VERSION 5.7 ;
  NOWIREEXTENSIONATPIN ON ;
  DIVIDERCHAR "/" ;
  BUSBITCHARS "[]" ;
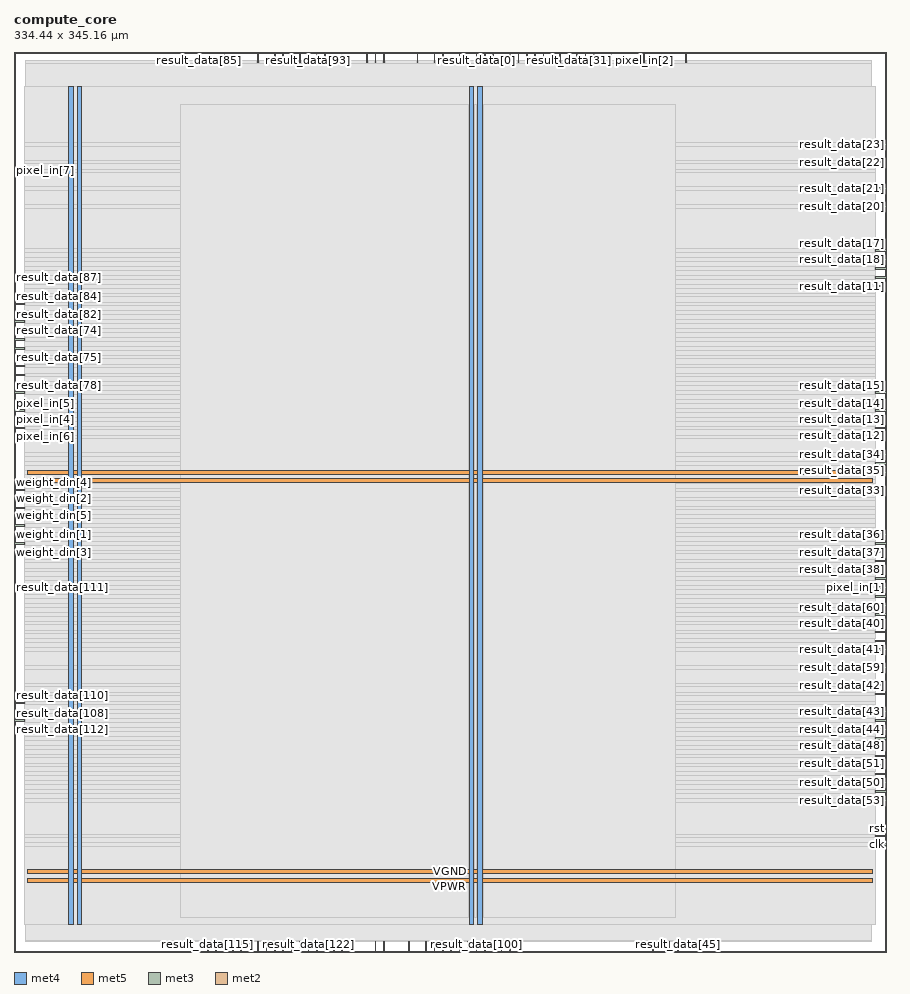
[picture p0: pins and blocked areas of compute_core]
MACRO compute_core
  CLASS BLOCK ;
  FOREIGN compute_core ;
  ORIGIN 0.000 0.000 ;
  SIZE 334.440 BY 345.160 ;
  PIN VGND
    DIRECTION INOUT ;
    USE GROUND ;
    PORT
      LAYER met4 ;
        RECT 24.340 10.640 25.940 332.080 ;
    END
    PORT
      LAYER met4 ;
        RECT 177.940 10.640 179.540 332.080 ;
    END
    PORT
      LAYER met5 ;
        RECT 5.280 30.030 329.140 31.630 ;
    END
    PORT
      LAYER met5 ;
        RECT 5.280 183.210 329.140 184.810 ;
    END
  END VGND
  PIN VPWR
    DIRECTION INOUT ;
    USE POWER ;
    PORT
      LAYER met4 ;
        RECT 21.040 10.640 22.640 332.080 ;
    END
    PORT
      LAYER met4 ;
        RECT 174.640 10.640 176.240 332.080 ;
    END
    PORT
      LAYER met5 ;
        RECT 5.280 26.730 329.140 28.330 ;
    END
    PORT
      LAYER met5 ;
        RECT 5.280 179.910 329.140 181.510 ;
    END
  END VPWR
  PIN clk
    DIRECTION INPUT ;
    USE SIGNAL ;
    ANTENNAGATEAREA 0.852000 ;
    PORT
      LAYER met3 ;
        RECT 330.440 40.840 334.440 41.440 ;
    END
  END clk
  PIN pixel_in[0]
    DIRECTION INPUT ;
    USE SIGNAL ;
    ANTENNAGATEAREA 0.213000 ;
    PORT
      LAYER met3 ;
        RECT 330.440 122.440 334.440 123.040 ;
    END
  END pixel_in[0]
  PIN pixel_in[1]
    DIRECTION INPUT ;
    USE SIGNAL ;
    ANTENNAGATEAREA 0.742500 ;
    PORT
      LAYER met3 ;
        RECT 330.440 139.440 334.440 140.040 ;
    END
  END pixel_in[1]
  PIN pixel_in[2]
    DIRECTION INPUT ;
    USE SIGNAL ;
    ANTENNAGATEAREA 0.213000 ;
    PORT
      LAYER met2 ;
        RECT 241.590 341.160 241.870 345.160 ;
    END
  END pixel_in[2]
  PIN pixel_in[3]
    DIRECTION INPUT ;
    USE SIGNAL ;
    ANTENNAGATEAREA 0.495000 ;
    PORT
      LAYER met3 ;
        RECT 0.000 200.640 4.000 201.240 ;
    END
  END pixel_in[3]
  PIN pixel_in[4]
    DIRECTION INPUT ;
    USE SIGNAL ;
    ANTENNAGATEAREA 0.213000 ;
    PORT
      LAYER met3 ;
        RECT 0.000 204.040 4.000 204.640 ;
    END
  END pixel_in[4]
  PIN pixel_in[5]
    DIRECTION INPUT ;
    USE SIGNAL ;
    ANTENNAGATEAREA 0.495000 ;
    PORT
      LAYER met3 ;
        RECT 0.000 207.440 4.000 208.040 ;
    END
  END pixel_in[5]
  PIN pixel_in[6]
    DIRECTION INPUT ;
    USE SIGNAL ;
    ANTENNAGATEAREA 0.196500 ;
    PORT
      LAYER met3 ;
        RECT 0.000 197.240 4.000 197.840 ;
    END
  END pixel_in[6]
  PIN pixel_in[7]
    DIRECTION INPUT ;
    USE SIGNAL ;
    ANTENNAGATEAREA 0.742500 ;
    PORT
      LAYER met3 ;
        RECT 0.000 299.240 4.000 299.840 ;
    END
  END pixel_in[7]
  PIN result_data[0]
    DIRECTION OUTPUT ;
    USE SIGNAL ;
    ANTENNADIFFAREA 0.445500 ;
    PORT
      LAYER met2 ;
        RECT 177.190 341.160 177.470 345.160 ;
    END
  END result_data[0]
  PIN result_data[100]
    DIRECTION OUTPUT ;
    USE SIGNAL ;
    ANTENNADIFFAREA 0.445500 ;
    PORT
      LAYER met2 ;
        RECT 177.190 0.000 177.470 4.000 ;
    END
  END result_data[100]
  PIN result_data[101]
    DIRECTION OUTPUT ;
    USE SIGNAL ;
    ANTENNADIFFAREA 0.445500 ;
    PORT
      LAYER met2 ;
        RECT 164.310 0.000 164.590 4.000 ;
    END
  END result_data[101]
  PIN result_data[102]
    DIRECTION OUTPUT ;
    USE SIGNAL ;
    ANTENNADIFFAREA 0.445500 ;
    PORT
      LAYER met2 ;
        RECT 151.430 0.000 151.710 4.000 ;
    END
  END result_data[102]
  PIN result_data[103]
    DIRECTION OUTPUT ;
    USE SIGNAL ;
    ANTENNADIFFAREA 0.445500 ;
    PORT
      LAYER met2 ;
        RECT 141.770 0.000 142.050 4.000 ;
    END
  END result_data[103]
  PIN result_data[104]
    DIRECTION OUTPUT ;
    USE SIGNAL ;
    ANTENNADIFFAREA 0.445500 ;
    PORT
      LAYER met2 ;
        RECT 138.550 0.000 138.830 4.000 ;
    END
  END result_data[104]
  PIN result_data[105]
    DIRECTION OUTPUT ;
    USE SIGNAL ;
    ANTENNADIFFAREA 0.445500 ;
    PORT
      LAYER met2 ;
        RECT 125.670 0.000 125.950 4.000 ;
    END
  END result_data[105]
  PIN result_data[106]
    DIRECTION OUTPUT ;
    USE SIGNAL ;
    ANTENNADIFFAREA 0.445500 ;
    PORT
      LAYER met2 ;
        RECT 109.570 0.000 109.850 4.000 ;
    END
  END result_data[106]
  PIN result_data[107]
    DIRECTION OUTPUT ;
    USE SIGNAL ;
    ANTENNADIFFAREA 0.445500 ;
    PORT
      LAYER met2 ;
        RECT 103.130 0.000 103.410 4.000 ;
    END
  END result_data[107]
  PIN result_data[108]
    DIRECTION OUTPUT ;
    USE SIGNAL ;
    ANTENNADIFFAREA 0.445500 ;
    PORT
      LAYER met3 ;
        RECT 0.000 88.440 4.000 89.040 ;
    END
  END result_data[108]
  PIN result_data[109]
    DIRECTION OUTPUT ;
    USE SIGNAL ;
    ANTENNADIFFAREA 0.445500 ;
    PORT
      LAYER met2 ;
        RECT 90.250 0.000 90.530 4.000 ;
    END
  END result_data[109]
  PIN result_data[10]
    DIRECTION OUTPUT ;
    USE SIGNAL ;
    ANTENNADIFFAREA 0.445500 ;
    PORT
      LAYER met3 ;
        RECT 330.440 261.840 334.440 262.440 ;
    END
  END result_data[10]
  PIN result_data[110]
    DIRECTION OUTPUT ;
    USE SIGNAL ;
    ANTENNADIFFAREA 0.445500 ;
    PORT
      LAYER met3 ;
        RECT 0.000 95.240 4.000 95.840 ;
    END
  END result_data[110]
  PIN result_data[111]
    DIRECTION OUTPUT ;
    USE SIGNAL ;
    ANTENNADIFFAREA 0.445500 ;
    PORT
      LAYER met3 ;
        RECT 0.000 139.440 4.000 140.040 ;
    END
  END result_data[111]
  PIN result_data[112]
    DIRECTION OUTPUT ;
    USE SIGNAL ;
    ANTENNADIFFAREA 0.445500 ;
    PORT
      LAYER met3 ;
        RECT 0.000 85.040 4.000 85.640 ;
    END
  END result_data[112]
  PIN result_data[113]
    DIRECTION OUTPUT ;
    USE SIGNAL ;
    ANTENNADIFFAREA 0.445500 ;
    PORT
      LAYER met2 ;
        RECT 80.590 0.000 80.870 4.000 ;
    END
  END result_data[113]
  PIN result_data[114]
    DIRECTION OUTPUT ;
    USE SIGNAL ;
    ANTENNADIFFAREA 0.445500 ;
    PORT
      LAYER met2 ;
        RECT 93.470 0.000 93.750 4.000 ;
    END
  END result_data[114]
  PIN result_data[115]
    DIRECTION OUTPUT ;
    USE SIGNAL ;
    ANTENNADIFFAREA 0.445500 ;
    PORT
      LAYER met2 ;
        RECT 74.150 0.000 74.430 4.000 ;
    END
  END result_data[115]
  PIN result_data[116]
    DIRECTION OUTPUT ;
    USE SIGNAL ;
    ANTENNADIFFAREA 0.445500 ;
    PORT
      LAYER met2 ;
        RECT 77.370 0.000 77.650 4.000 ;
    END
  END result_data[116]
  PIN result_data[117]
    DIRECTION OUTPUT ;
    USE SIGNAL ;
    ANTENNADIFFAREA 0.445500 ;
    PORT
      LAYER met2 ;
        RECT 87.030 0.000 87.310 4.000 ;
    END
  END result_data[117]
  PIN result_data[118]
    DIRECTION OUTPUT ;
    USE SIGNAL ;
    ANTENNADIFFAREA 0.445500 ;
    PORT
      LAYER met2 ;
        RECT 83.810 0.000 84.090 4.000 ;
    END
  END result_data[118]
  PIN result_data[119]
    DIRECTION OUTPUT ;
    USE SIGNAL ;
    ANTENNADIFFAREA 0.445500 ;
    PORT
      LAYER met2 ;
        RECT 96.690 0.000 96.970 4.000 ;
    END
  END result_data[119]
  PIN result_data[11]
    DIRECTION OUTPUT ;
    USE SIGNAL ;
    ANTENNADIFFAREA 0.445500 ;
    PORT
      LAYER met3 ;
        RECT 330.440 255.040 334.440 255.640 ;
    END
  END result_data[11]
  PIN result_data[120]
    DIRECTION OUTPUT ;
    USE SIGNAL ;
    ANTENNADIFFAREA 0.445500 ;
    PORT
      LAYER met2 ;
        RECT 99.910 0.000 100.190 4.000 ;
    END
  END result_data[120]
  PIN result_data[121]
    DIRECTION OUTPUT ;
    USE SIGNAL ;
    ANTENNADIFFAREA 0.445500 ;
    PORT
      LAYER met2 ;
        RECT 106.350 0.000 106.630 4.000 ;
    END
  END result_data[121]
  PIN result_data[122]
    DIRECTION OUTPUT ;
    USE SIGNAL ;
    ANTENNADIFFAREA 0.445500 ;
    PORT
      LAYER met2 ;
        RECT 112.790 0.000 113.070 4.000 ;
    END
  END result_data[122]
  PIN result_data[123]
    DIRECTION OUTPUT ;
    USE SIGNAL ;
    ANTENNADIFFAREA 0.445500 ;
    PORT
      LAYER met2 ;
        RECT 116.010 0.000 116.290 4.000 ;
    END
  END result_data[123]
  PIN result_data[124]
    DIRECTION OUTPUT ;
    USE SIGNAL ;
    ANTENNADIFFAREA 0.445500 ;
    PORT
      LAYER met2 ;
        RECT 122.450 0.000 122.730 4.000 ;
    END
  END result_data[124]
  PIN result_data[125]
    DIRECTION OUTPUT ;
    USE SIGNAL ;
    ANTENNADIFFAREA 0.445500 ;
    PORT
      LAYER met2 ;
        RECT 173.970 0.000 174.250 4.000 ;
    END
  END result_data[125]
  PIN result_data[126]
    DIRECTION OUTPUT ;
    USE SIGNAL ;
    ANTENNADIFFAREA 0.445500 ;
    PORT
      LAYER met2 ;
        RECT 167.530 0.000 167.810 4.000 ;
    END
  END result_data[126]
  PIN result_data[127]
    DIRECTION OUTPUT ;
    USE SIGNAL ;
    ANTENNADIFFAREA 0.445500 ;
    PORT
      LAYER met2 ;
        RECT 170.750 0.000 171.030 4.000 ;
    END
  END result_data[127]
  PIN result_data[12]
    DIRECTION OUTPUT ;
    USE SIGNAL ;
    ANTENNADIFFAREA 0.445500 ;
    PORT
      LAYER met3 ;
        RECT 330.440 200.640 334.440 201.240 ;
    END
  END result_data[12]
  PIN result_data[13]
    DIRECTION OUTPUT ;
    USE SIGNAL ;
    ANTENNADIFFAREA 0.445500 ;
    PORT
      LAYER met3 ;
        RECT 330.440 204.040 334.440 204.640 ;
    END
  END result_data[13]
  PIN result_data[14]
    DIRECTION OUTPUT ;
    USE SIGNAL ;
    ANTENNADIFFAREA 0.445500 ;
    PORT
      LAYER met3 ;
        RECT 330.440 207.440 334.440 208.040 ;
    END
  END result_data[14]
  PIN result_data[15]
    DIRECTION OUTPUT ;
    USE SIGNAL ;
    ANTENNADIFFAREA 0.445500 ;
    PORT
      LAYER met3 ;
        RECT 330.440 214.240 334.440 214.840 ;
    END
  END result_data[15]
  PIN result_data[16]
    DIRECTION OUTPUT ;
    USE SIGNAL ;
    ANTENNADIFFAREA 0.445500 ;
    PORT
      LAYER met3 ;
        RECT 330.440 258.440 334.440 259.040 ;
    END
  END result_data[16]
  PIN result_data[17]
    DIRECTION OUTPUT ;
    USE SIGNAL ;
    ANTENNADIFFAREA 0.445500 ;
    PORT
      LAYER met3 ;
        RECT 330.440 268.640 334.440 269.240 ;
    END
  END result_data[17]
  PIN result_data[18]
    DIRECTION OUTPUT ;
    USE SIGNAL ;
    ANTENNADIFFAREA 0.445500 ;
    PORT
      LAYER met3 ;
        RECT 330.440 265.240 334.440 265.840 ;
    END
  END result_data[18]
  PIN result_data[19]
    DIRECTION OUTPUT ;
    USE SIGNAL ;
    ANTENNADIFFAREA 0.445500 ;
    PORT
      LAYER met2 ;
        RECT 257.690 341.160 257.970 345.160 ;
    END
  END result_data[19]
  PIN result_data[1]
    DIRECTION OUTPUT ;
    USE SIGNAL ;
    ANTENNADIFFAREA 0.445500 ;
    PORT
      LAYER met2 ;
        RECT 170.750 341.160 171.030 345.160 ;
    END
  END result_data[1]
  PIN result_data[20]
    DIRECTION OUTPUT ;
    USE SIGNAL ;
    ANTENNADIFFAREA 0.445500 ;
    PORT
      LAYER met3 ;
        RECT 330.440 285.640 334.440 286.240 ;
    END
  END result_data[20]
  PIN result_data[21]
    DIRECTION OUTPUT ;
    USE SIGNAL ;
    ANTENNADIFFAREA 0.445500 ;
    PORT
      LAYER met3 ;
        RECT 330.440 292.440 334.440 293.040 ;
    END
  END result_data[21]
  PIN result_data[22]
    DIRECTION OUTPUT ;
    USE SIGNAL ;
    ANTENNADIFFAREA 0.445500 ;
    PORT
      LAYER met3 ;
        RECT 330.440 302.640 334.440 303.240 ;
    END
  END result_data[22]
  PIN result_data[23]
    DIRECTION OUTPUT ;
    USE SIGNAL ;
    ANTENNADIFFAREA 0.445500 ;
    PORT
      LAYER met3 ;
        RECT 330.440 309.440 334.440 310.040 ;
    END
  END result_data[23]
  PIN result_data[24]
    DIRECTION OUTPUT ;
    USE SIGNAL ;
    ANTENNADIFFAREA 0.445500 ;
    PORT
      LAYER met2 ;
        RECT 248.030 341.160 248.310 345.160 ;
    END
  END result_data[24]
  PIN result_data[25]
    DIRECTION OUTPUT ;
    USE SIGNAL ;
    ANTENNADIFFAREA 0.445500 ;
    PORT
      LAYER met2 ;
        RECT 225.490 341.160 225.770 345.160 ;
    END
  END result_data[25]
  PIN result_data[26]
    DIRECTION OUTPUT ;
    USE SIGNAL ;
    ANTENNADIFFAREA 0.445500 ;
    PORT
      LAYER met2 ;
        RECT 180.410 341.160 180.690 345.160 ;
    END
  END result_data[26]
  PIN result_data[27]
    DIRECTION OUTPUT ;
    USE SIGNAL ;
    ANTENNADIFFAREA 0.445500 ;
    PORT
      LAYER met2 ;
        RECT 196.510 341.160 196.790 345.160 ;
    END
  END result_data[27]
  PIN result_data[28]
    DIRECTION OUTPUT ;
    USE SIGNAL ;
    ANTENNADIFFAREA 0.445500 ;
    PORT
      LAYER met2 ;
        RECT 206.170 341.160 206.450 345.160 ;
    END
  END result_data[28]
  PIN result_data[29]
    DIRECTION OUTPUT ;
    USE SIGNAL ;
    ANTENNADIFFAREA 0.445500 ;
    PORT
      LAYER met2 ;
        RECT 209.390 341.160 209.670 345.160 ;
    END
  END result_data[29]
  PIN result_data[2]
    DIRECTION OUTPUT ;
    USE SIGNAL ;
    ANTENNADIFFAREA 0.445500 ;
    PORT
      LAYER met2 ;
        RECT 183.630 341.160 183.910 345.160 ;
    END
  END result_data[2]
  PIN result_data[30]
    DIRECTION OUTPUT ;
    USE SIGNAL ;
    ANTENNADIFFAREA 0.445500 ;
    PORT
      LAYER met2 ;
        RECT 186.850 341.160 187.130 345.160 ;
    END
  END result_data[30]
  PIN result_data[31]
    DIRECTION OUTPUT ;
    USE SIGNAL ;
    ANTENNADIFFAREA 0.445500 ;
    PORT
      LAYER met2 ;
        RECT 212.610 341.160 212.890 345.160 ;
    END
  END result_data[31]
  PIN result_data[32]
    DIRECTION OUTPUT ;
    USE SIGNAL ;
    ANTENNADIFFAREA 0.445500 ;
    PORT
      LAYER met3 ;
        RECT 330.440 183.640 334.440 184.240 ;
    END
  END result_data[32]
  PIN result_data[33]
    DIRECTION OUTPUT ;
    USE SIGNAL ;
    ANTENNADIFFAREA 0.445500 ;
    PORT
      LAYER met3 ;
        RECT 330.440 176.840 334.440 177.440 ;
    END
  END result_data[33]
  PIN result_data[34]
    DIRECTION OUTPUT ;
    USE SIGNAL ;
    ANTENNADIFFAREA 0.445500 ;
    PORT
      LAYER met3 ;
        RECT 330.440 190.440 334.440 191.040 ;
    END
  END result_data[34]
  PIN result_data[35]
    DIRECTION OUTPUT ;
    USE SIGNAL ;
    ANTENNADIFFAREA 0.445500 ;
    PORT
      LAYER met3 ;
        RECT 330.440 187.040 334.440 187.640 ;
    END
  END result_data[35]
  PIN result_data[36]
    DIRECTION OUTPUT ;
    USE SIGNAL ;
    ANTENNADIFFAREA 0.445500 ;
    PORT
      LAYER met3 ;
        RECT 330.440 159.840 334.440 160.440 ;
    END
  END result_data[36]
  PIN result_data[37]
    DIRECTION OUTPUT ;
    USE SIGNAL ;
    ANTENNADIFFAREA 0.445500 ;
    PORT
      LAYER met3 ;
        RECT 330.440 153.040 334.440 153.640 ;
    END
  END result_data[37]
  PIN result_data[38]
    DIRECTION OUTPUT ;
    USE SIGNAL ;
    ANTENNADIFFAREA 0.445500 ;
    PORT
      LAYER met3 ;
        RECT 330.440 146.240 334.440 146.840 ;
    END
  END result_data[38]
  PIN result_data[39]
    DIRECTION OUTPUT ;
    USE SIGNAL ;
    ANTENNADIFFAREA 0.445500 ;
    PORT
      LAYER met3 ;
        RECT 330.440 132.640 334.440 133.240 ;
    END
  END result_data[39]
  PIN result_data[3]
    DIRECTION OUTPUT ;
    USE SIGNAL ;
    ANTENNADIFFAREA 0.445500 ;
    PORT
      LAYER met2 ;
        RECT 193.290 341.160 193.570 345.160 ;
    END
  END result_data[3]
  PIN result_data[40]
    DIRECTION OUTPUT ;
    USE SIGNAL ;
    ANTENNADIFFAREA 0.445500 ;
    PORT
      LAYER met3 ;
        RECT 330.440 125.840 334.440 126.440 ;
    END
  END result_data[40]
  PIN result_data[41]
    DIRECTION OUTPUT ;
    USE SIGNAL ;
    ANTENNADIFFAREA 0.445500 ;
    PORT
      LAYER met3 ;
        RECT 330.440 115.640 334.440 116.240 ;
    END
  END result_data[41]
  PIN result_data[42]
    DIRECTION OUTPUT ;
    USE SIGNAL ;
    ANTENNADIFFAREA 0.445500 ;
    PORT
      LAYER met3 ;
        RECT 330.440 102.040 334.440 102.640 ;
    END
  END result_data[42]
  PIN result_data[43]
    DIRECTION OUTPUT ;
    USE SIGNAL ;
    ANTENNADIFFAREA 0.445500 ;
    PORT
      LAYER met3 ;
        RECT 330.440 91.840 334.440 92.440 ;
    END
  END result_data[43]
  PIN result_data[44]
    DIRECTION OUTPUT ;
    USE SIGNAL ;
    ANTENNADIFFAREA 0.445500 ;
    PORT
      LAYER met3 ;
        RECT 330.440 85.040 334.440 85.640 ;
    END
  END result_data[44]
  PIN result_data[45]
    DIRECTION OUTPUT ;
    USE SIGNAL ;
    ANTENNADIFFAREA 0.445500 ;
    PORT
      LAYER met2 ;
        RECT 254.470 0.000 254.750 4.000 ;
    END
  END result_data[45]
  PIN result_data[46]
    DIRECTION OUTPUT ;
    USE SIGNAL ;
    ANTENNADIFFAREA 0.445500 ;
    PORT
      LAYER met2 ;
        RECT 244.810 0.000 245.090 4.000 ;
    END
  END result_data[46]
  PIN result_data[47]
    DIRECTION OUTPUT ;
    USE SIGNAL ;
    ANTENNADIFFAREA 0.445500 ;
    PORT
      LAYER met2 ;
        RECT 251.250 0.000 251.530 4.000 ;
    END
  END result_data[47]
  PIN result_data[48]
    DIRECTION OUTPUT ;
    USE SIGNAL ;
    ANTENNADIFFAREA 0.445500 ;
    PORT
      LAYER met3 ;
        RECT 330.440 81.640 334.440 82.240 ;
    END
  END result_data[48]
  PIN result_data[49]
    DIRECTION OUTPUT ;
    USE SIGNAL ;
    ANTENNADIFFAREA 0.445500 ;
    PORT
      LAYER met3 ;
        RECT 330.440 71.440 334.440 72.040 ;
    END
  END result_data[49]
  PIN result_data[4]
    DIRECTION OUTPUT ;
    USE SIGNAL ;
    ANTENNADIFFAREA 0.445500 ;
    PORT
      LAYER met2 ;
        RECT 199.730 341.160 200.010 345.160 ;
    END
  END result_data[4]
  PIN result_data[50]
    DIRECTION OUTPUT ;
    USE SIGNAL ;
    ANTENNADIFFAREA 0.445500 ;
    PORT
      LAYER met3 ;
        RECT 330.440 64.640 334.440 65.240 ;
    END
  END result_data[50]
  PIN result_data[51]
    DIRECTION OUTPUT ;
    USE SIGNAL ;
    ANTENNADIFFAREA 0.445500 ;
    PORT
      LAYER met3 ;
        RECT 330.440 74.840 334.440 75.440 ;
    END
  END result_data[51]
  PIN result_data[52]
    DIRECTION OUTPUT ;
    USE SIGNAL ;
    ANTENNADIFFAREA 0.445500 ;
    PORT
      LAYER met3 ;
        RECT 330.440 61.240 334.440 61.840 ;
    END
  END result_data[52]
  PIN result_data[53]
    DIRECTION OUTPUT ;
    USE SIGNAL ;
    ANTENNADIFFAREA 0.445500 ;
    PORT
      LAYER met3 ;
        RECT 330.440 57.840 334.440 58.440 ;
    END
  END result_data[53]
  PIN result_data[54]
    DIRECTION OUTPUT ;
    USE SIGNAL ;
    ANTENNADIFFAREA 0.445500 ;
    PORT
      LAYER met3 ;
        RECT 330.440 68.040 334.440 68.640 ;
    END
  END result_data[54]
  PIN result_data[55]
    DIRECTION OUTPUT ;
    USE SIGNAL ;
    ANTENNADIFFAREA 0.445500 ;
    PORT
      LAYER met3 ;
        RECT 330.440 78.240 334.440 78.840 ;
    END
  END result_data[55]
  PIN result_data[56]
    DIRECTION OUTPUT ;
    USE SIGNAL ;
    ANTENNADIFFAREA 0.445500 ;
    PORT
      LAYER met3 ;
        RECT 330.440 88.440 334.440 89.040 ;
    END
  END result_data[56]
  PIN result_data[57]
    DIRECTION OUTPUT ;
    USE SIGNAL ;
    ANTENNADIFFAREA 0.445500 ;
    PORT
      LAYER met3 ;
        RECT 330.440 98.640 334.440 99.240 ;
    END
  END result_data[57]
  PIN result_data[58]
    DIRECTION OUTPUT ;
    USE SIGNAL ;
    ANTENNADIFFAREA 0.445500 ;
    PORT
      LAYER met3 ;
        RECT 330.440 119.040 334.440 119.640 ;
    END
  END result_data[58]
  PIN result_data[59]
    DIRECTION OUTPUT ;
    USE SIGNAL ;
    ANTENNADIFFAREA 0.445500 ;
    PORT
      LAYER met3 ;
        RECT 330.440 108.840 334.440 109.440 ;
    END
  END result_data[59]
  PIN result_data[5]
    DIRECTION OUTPUT ;
    USE SIGNAL ;
    ANTENNADIFFAREA 0.445500 ;
    PORT
      LAYER met2 ;
        RECT 202.950 341.160 203.230 345.160 ;
    END
  END result_data[5]
  PIN result_data[60]
    DIRECTION OUTPUT ;
    USE SIGNAL ;
    ANTENNADIFFAREA 0.445500 ;
    PORT
      LAYER met3 ;
        RECT 330.440 129.240 334.440 129.840 ;
    END
  END result_data[60]
  PIN result_data[61]
    DIRECTION OUTPUT ;
    USE SIGNAL ;
    ANTENNADIFFAREA 0.445500 ;
    PORT
      LAYER met3 ;
        RECT 330.440 136.040 334.440 136.640 ;
    END
  END result_data[61]
  PIN result_data[62]
    DIRECTION OUTPUT ;
    USE SIGNAL ;
    ANTENNADIFFAREA 0.445500 ;
    PORT
      LAYER met3 ;
        RECT 330.440 149.640 334.440 150.240 ;
    END
  END result_data[62]
  PIN result_data[63]
    DIRECTION OUTPUT ;
    USE SIGNAL ;
    ANTENNADIFFAREA 0.445500 ;
    PORT
      LAYER met3 ;
        RECT 330.440 156.440 334.440 157.040 ;
    END
  END result_data[63]
  PIN result_data[64]
    DIRECTION OUTPUT ;
    USE SIGNAL ;
    ANTENNADIFFAREA 0.445500 ;
    PORT
      LAYER met2 ;
        RECT 154.650 341.160 154.930 345.160 ;
    END
  END result_data[64]
  PIN result_data[65]
    DIRECTION OUTPUT ;
    USE SIGNAL ;
    ANTENNADIFFAREA 0.445500 ;
    PORT
      LAYER met2 ;
        RECT 161.090 341.160 161.370 345.160 ;
    END
  END result_data[65]
  PIN result_data[66]
    DIRECTION OUTPUT ;
    USE SIGNAL ;
    ANTENNADIFFAREA 0.445500 ;
    PORT
      LAYER met2 ;
        RECT 141.770 341.160 142.050 345.160 ;
    END
  END result_data[66]
  PIN result_data[67]
    DIRECTION OUTPUT ;
    USE SIGNAL ;
    ANTENNADIFFAREA 0.445500 ;
    PORT
      LAYER met2 ;
        RECT 125.670 341.160 125.950 345.160 ;
    END
  END result_data[67]
  PIN result_data[68]
    DIRECTION OUTPUT ;
    USE SIGNAL ;
    ANTENNADIFFAREA 0.445500 ;
    PORT
      LAYER met2 ;
        RECT 164.310 341.160 164.590 345.160 ;
    END
  END result_data[68]
  PIN result_data[69]
    DIRECTION OUTPUT ;
    USE SIGNAL ;
    ANTENNADIFFAREA 0.445500 ;
    PORT
      LAYER met2 ;
        RECT 116.010 341.160 116.290 345.160 ;
    END
  END result_data[69]
  PIN result_data[6]
    DIRECTION OUTPUT ;
    USE SIGNAL ;
    ANTENNADIFFAREA 0.445500 ;
    PORT
      LAYER met2 ;
        RECT 222.270 341.160 222.550 345.160 ;
    END
  END result_data[6]
  PIN result_data[70]
    DIRECTION OUTPUT ;
    USE SIGNAL ;
    ANTENNADIFFAREA 0.445500 ;
    PORT
      LAYER met2 ;
        RECT 106.350 341.160 106.630 345.160 ;
    END
  END result_data[70]
  PIN result_data[71]
    DIRECTION OUTPUT ;
    USE SIGNAL ;
    ANTENNADIFFAREA 0.445500 ;
    PORT
      LAYER met2 ;
        RECT 109.570 341.160 109.850 345.160 ;
    END
  END result_data[71]
  PIN result_data[72]
    DIRECTION OUTPUT ;
    USE SIGNAL ;
    ANTENNADIFFAREA 0.445500 ;
    PORT
      LAYER met2 ;
        RECT 119.230 341.160 119.510 345.160 ;
    END
  END result_data[72]
  PIN result_data[73]
    DIRECTION OUTPUT ;
    USE SIGNAL ;
    ANTENNADIFFAREA 0.445500 ;
    PORT
      LAYER met3 ;
        RECT 0.000 217.640 4.000 218.240 ;
    END
  END result_data[73]
  PIN result_data[74]
    DIRECTION OUTPUT ;
    USE SIGNAL ;
    ANTENNADIFFAREA 0.445500 ;
    PORT
      LAYER met3 ;
        RECT 0.000 238.040 4.000 238.640 ;
    END
  END result_data[74]
  PIN result_data[75]
    DIRECTION OUTPUT ;
    USE SIGNAL ;
    ANTENNADIFFAREA 0.445500 ;
    PORT
      LAYER met3 ;
        RECT 0.000 227.840 4.000 228.440 ;
    END
  END result_data[75]
  PIN result_data[76]
    DIRECTION OUTPUT ;
    USE SIGNAL ;
    ANTENNADIFFAREA 0.445500 ;
    PORT
      LAYER met3 ;
        RECT 0.000 231.240 4.000 231.840 ;
    END
  END result_data[76]
  PIN result_data[77]
    DIRECTION OUTPUT ;
    USE SIGNAL ;
    ANTENNADIFFAREA 0.445500 ;
    PORT
      LAYER met3 ;
        RECT 0.000 210.840 4.000 211.440 ;
    END
  END result_data[77]
  PIN result_data[78]
    DIRECTION OUTPUT ;
    USE SIGNAL ;
    ANTENNADIFFAREA 0.445500 ;
    PORT
      LAYER met3 ;
        RECT 0.000 214.240 4.000 214.840 ;
    END
  END result_data[78]
  PIN result_data[79]
    DIRECTION OUTPUT ;
    USE SIGNAL ;
    ANTENNADIFFAREA 0.445500 ;
    PORT
      LAYER met3 ;
        RECT 0.000 221.040 4.000 221.640 ;
    END
  END result_data[79]
  PIN result_data[7]
    DIRECTION OUTPUT ;
    USE SIGNAL ;
    ANTENNADIFFAREA 0.445500 ;
    PORT
      LAYER met2 ;
        RECT 215.830 341.160 216.110 345.160 ;
    END
  END result_data[7]
  PIN result_data[80]
    DIRECTION OUTPUT ;
    USE SIGNAL ;
    ANTENNADIFFAREA 0.445500 ;
    PORT
      LAYER met3 ;
        RECT 0.000 224.440 4.000 225.040 ;
    END
  END result_data[80]
  PIN result_data[81]
    DIRECTION OUTPUT ;
    USE SIGNAL ;
    ANTENNADIFFAREA 0.445500 ;
    PORT
      LAYER met3 ;
        RECT 0.000 234.640 4.000 235.240 ;
    END
  END result_data[81]
  PIN result_data[82]
    DIRECTION OUTPUT ;
    USE SIGNAL ;
    ANTENNADIFFAREA 0.445500 ;
    PORT
      LAYER met3 ;
        RECT 0.000 241.440 4.000 242.040 ;
    END
  END result_data[82]
  PIN result_data[83]
    DIRECTION OUTPUT ;
    USE SIGNAL ;
    ANTENNADIFFAREA 0.445500 ;
    PORT
      LAYER met3 ;
        RECT 0.000 244.840 4.000 245.440 ;
    END
  END result_data[83]
  PIN result_data[84]
    DIRECTION OUTPUT ;
    USE SIGNAL ;
    ANTENNADIFFAREA 0.445500 ;
    PORT
      LAYER met3 ;
        RECT 0.000 248.240 4.000 248.840 ;
    END
  END result_data[84]
  PIN result_data[85]
    DIRECTION OUTPUT ;
    USE SIGNAL ;
    ANTENNADIFFAREA 0.445500 ;
    PORT
      LAYER met2 ;
        RECT 70.930 341.160 71.210 345.160 ;
    END
  END result_data[85]
  PIN result_data[86]
    DIRECTION OUTPUT ;
    USE SIGNAL ;
    ANTENNADIFFAREA 0.445500 ;
    PORT
      LAYER met3 ;
        RECT 0.000 251.640 4.000 252.240 ;
    END
  END result_data[86]
  PIN result_data[87]
    DIRECTION OUTPUT ;
    USE SIGNAL ;
    ANTENNADIFFAREA 0.445500 ;
    PORT
      LAYER met3 ;
        RECT 0.000 258.440 4.000 259.040 ;
    END
  END result_data[87]
  PIN result_data[88]
    DIRECTION OUTPUT ;
    USE SIGNAL ;
    ANTENNADIFFAREA 0.445500 ;
    PORT
      LAYER met2 ;
        RECT 83.810 341.160 84.090 345.160 ;
    END
  END result_data[88]
  PIN result_data[89]
    DIRECTION OUTPUT ;
    USE SIGNAL ;
    ANTENNADIFFAREA 0.445500 ;
    PORT
      LAYER met2 ;
        RECT 80.590 341.160 80.870 345.160 ;
    END
  END result_data[89]
  PIN result_data[8]
    DIRECTION OUTPUT ;
    USE SIGNAL ;
    ANTENNADIFFAREA 0.445500 ;
    PORT
      LAYER met2 ;
        RECT 219.050 341.160 219.330 345.160 ;
    END
  END result_data[8]
  PIN result_data[90]
    DIRECTION OUTPUT ;
    USE SIGNAL ;
    ANTENNADIFFAREA 0.445500 ;
    PORT
      LAYER met2 ;
        RECT 93.470 341.160 93.750 345.160 ;
    END
  END result_data[90]
  PIN result_data[91]
    DIRECTION OUTPUT ;
    USE SIGNAL ;
    ANTENNADIFFAREA 0.445500 ;
    PORT
      LAYER met2 ;
        RECT 99.910 341.160 100.190 345.160 ;
    END
  END result_data[91]
  PIN result_data[92]
    DIRECTION OUTPUT ;
    USE SIGNAL ;
    ANTENNADIFFAREA 0.445500 ;
    PORT
      LAYER met2 ;
        RECT 103.130 341.160 103.410 345.160 ;
    END
  END result_data[92]
  PIN result_data[93]
    DIRECTION OUTPUT ;
    USE SIGNAL ;
    ANTENNADIFFAREA 0.445500 ;
    PORT
      LAYER met2 ;
        RECT 112.790 341.160 113.070 345.160 ;
    END
  END result_data[93]
  PIN result_data[94]
    DIRECTION OUTPUT ;
    USE SIGNAL ;
    ANTENNADIFFAREA 0.445500 ;
    PORT
      LAYER met2 ;
        RECT 138.550 341.160 138.830 345.160 ;
    END
  END result_data[94]
  PIN result_data[95]
    DIRECTION OUTPUT ;
    USE SIGNAL ;
    ANTENNADIFFAREA 0.445500 ;
    PORT
      LAYER met2 ;
        RECT 135.330 341.160 135.610 345.160 ;
    END
  END result_data[95]
  PIN result_data[96]
    DIRECTION OUTPUT ;
    USE SIGNAL ;
    ANTENNADIFFAREA 0.445500 ;
    PORT
      LAYER met2 ;
        RECT 183.630 0.000 183.910 4.000 ;
    END
  END result_data[96]
  PIN result_data[97]
    DIRECTION OUTPUT ;
    USE SIGNAL ;
    ANTENNADIFFAREA 0.445500 ;
    PORT
      LAYER met2 ;
        RECT 186.850 0.000 187.130 4.000 ;
    END
  END result_data[97]
  PIN result_data[98]
    DIRECTION OUTPUT ;
    USE SIGNAL ;
    ANTENNADIFFAREA 0.445500 ;
    PORT
      LAYER met2 ;
        RECT 190.070 0.000 190.350 4.000 ;
    END
  END result_data[98]
  PIN result_data[99]
    DIRECTION OUTPUT ;
    USE SIGNAL ;
    ANTENNADIFFAREA 0.445500 ;
    PORT
      LAYER met2 ;
        RECT 180.410 0.000 180.690 4.000 ;
    END
  END result_data[99]
  PIN result_data[9]
    DIRECTION OUTPUT ;
    USE SIGNAL ;
    ANTENNADIFFAREA 0.445500 ;
    PORT
      LAYER met2 ;
        RECT 228.710 341.160 228.990 345.160 ;
    END
  END result_data[9]
  PIN result_valid
    DIRECTION OUTPUT ;
    USE SIGNAL ;
    ANTENNADIFFAREA 0.445500 ;
    PORT
      LAYER met2 ;
        RECT 190.070 341.160 190.350 345.160 ;
    END
  END result_valid
  PIN rst
    DIRECTION INPUT ;
    USE SIGNAL ;
    ANTENNAGATEAREA 0.159000 ;
    PORT
      LAYER met3 ;
        RECT 330.440 44.240 334.440 44.840 ;
    END
  END rst
  PIN valid_in
    DIRECTION INPUT ;
    USE SIGNAL ;
    ANTENNAGATEAREA 0.213000 ;
    PORT
      LAYER met3 ;
        RECT 330.440 142.840 334.440 143.440 ;
    END
  END valid_in
  PIN weight_addr[0]
    DIRECTION INPUT ;
    USE SIGNAL ;
    ANTENNAGATEAREA 0.159000 ;
    PORT
      LAYER met2 ;
        RECT 161.090 0.000 161.370 4.000 ;
    END
  END weight_addr[0]
  PIN weight_addr[1]
    DIRECTION INPUT ;
    USE SIGNAL ;
    ANTENNAGATEAREA 0.159000 ;
    PORT
      LAYER met3 ;
        RECT 0.000 166.640 4.000 167.240 ;
    END
  END weight_addr[1]
  PIN weight_din[0]
    DIRECTION INPUT ;
    USE SIGNAL ;
    ANTENNAGATEAREA 0.213000 ;
    PORT
      LAYER met2 ;
        RECT 157.870 0.000 158.150 4.000 ;
    END
  END weight_din[0]
  PIN weight_din[1]
    DIRECTION INPUT ;
    USE SIGNAL ;
    ANTENNAGATEAREA 0.159000 ;
    PORT
      LAYER met3 ;
        RECT 0.000 159.840 4.000 160.440 ;
    END
  END weight_din[1]
  PIN weight_din[2]
    DIRECTION INPUT ;
    USE SIGNAL ;
    ANTENNAGATEAREA 0.159000 ;
    PORT
      LAYER met3 ;
        RECT 0.000 173.440 4.000 174.040 ;
    END
  END weight_din[2]
  PIN weight_din[3]
    DIRECTION INPUT ;
    USE SIGNAL ;
    ANTENNAGATEAREA 0.159000 ;
    PORT
      LAYER met3 ;
        RECT 0.000 153.040 4.000 153.640 ;
    END
  END weight_din[3]
  PIN weight_din[4]
    DIRECTION INPUT ;
    USE SIGNAL ;
    ANTENNAGATEAREA 0.213000 ;
    PORT
      LAYER met3 ;
        RECT 0.000 176.840 4.000 177.440 ;
    END
  END weight_din[4]
  PIN weight_din[5]
    DIRECTION INPUT ;
    USE SIGNAL ;
    ANTENNAGATEAREA 0.213000 ;
    PORT
      LAYER met3 ;
        RECT 0.000 170.040 4.000 170.640 ;
    END
  END weight_din[5]
  PIN weight_din[6]
    DIRECTION INPUT ;
    USE SIGNAL ;
    ANTENNAGATEAREA 0.213000 ;
    PORT
      LAYER met3 ;
        RECT 0.000 156.440 4.000 157.040 ;
    END
  END weight_din[6]
  PIN weight_din[7]
    DIRECTION INPUT ;
    USE SIGNAL ;
    ANTENNAGATEAREA 0.159000 ;
    PORT
      LAYER met3 ;
        RECT 0.000 180.240 4.000 180.840 ;
    END
  END weight_din[7]
  PIN weight_wr
    DIRECTION INPUT ;
    USE SIGNAL ;
    ANTENNAGATEAREA 0.213000 ;
    PORT
      LAYER met3 ;
        RECT 0.000 163.240 4.000 163.840 ;
    END
  END weight_wr
  OBS
      LAYER nwell ;
        RECT 5.330 10.795 329.090 331.925 ;
      LAYER li1 ;
        RECT 5.520 10.795 328.900 331.925 ;
      LAYER met1 ;
        RECT 4.210 10.640 329.200 332.080 ;
      LAYER met2 ;
        RECT 4.230 340.880 70.650 341.770 ;
        RECT 71.490 340.880 80.310 341.770 ;
        RECT 81.150 340.880 83.530 341.770 ;
        RECT 84.370 340.880 93.190 341.770 ;
        RECT 94.030 340.880 99.630 341.770 ;
        RECT 100.470 340.880 102.850 341.770 ;
        RECT 103.690 340.880 106.070 341.770 ;
        RECT 106.910 340.880 109.290 341.770 ;
        RECT 110.130 340.880 112.510 341.770 ;
        RECT 113.350 340.880 115.730 341.770 ;
        RECT 116.570 340.880 118.950 341.770 ;
        RECT 119.790 340.880 125.390 341.770 ;
        RECT 126.230 340.880 135.050 341.770 ;
        RECT 135.890 340.880 138.270 341.770 ;
        RECT 139.110 340.880 141.490 341.770 ;
        RECT 142.330 340.880 154.370 341.770 ;
        RECT 155.210 340.880 160.810 341.770 ;
        RECT 161.650 340.880 164.030 341.770 ;
        RECT 164.870 340.880 170.470 341.770 ;
        RECT 171.310 340.880 176.910 341.770 ;
        RECT 177.750 340.880 180.130 341.770 ;
        RECT 180.970 340.880 183.350 341.770 ;
        RECT 184.190 340.880 186.570 341.770 ;
        RECT 187.410 340.880 189.790 341.770 ;
        RECT 190.630 340.880 193.010 341.770 ;
        RECT 193.850 340.880 196.230 341.770 ;
        RECT 197.070 340.880 199.450 341.770 ;
        RECT 200.290 340.880 202.670 341.770 ;
        RECT 203.510 340.880 205.890 341.770 ;
        RECT 206.730 340.880 209.110 341.770 ;
        RECT 209.950 340.880 212.330 341.770 ;
        RECT 213.170 340.880 215.550 341.770 ;
        RECT 216.390 340.880 218.770 341.770 ;
        RECT 219.610 340.880 221.990 341.770 ;
        RECT 222.830 340.880 225.210 341.770 ;
        RECT 226.050 340.880 228.430 341.770 ;
        RECT 229.270 340.880 241.310 341.770 ;
        RECT 242.150 340.880 247.750 341.770 ;
        RECT 248.590 340.880 257.410 341.770 ;
        RECT 258.250 340.880 328.810 341.770 ;
        RECT 4.230 4.280 328.810 340.880 ;
        RECT 4.230 4.000 73.870 4.280 ;
        RECT 74.710 4.000 77.090 4.280 ;
        RECT 77.930 4.000 80.310 4.280 ;
        RECT 81.150 4.000 83.530 4.280 ;
        RECT 84.370 4.000 86.750 4.280 ;
        RECT 87.590 4.000 89.970 4.280 ;
        RECT 90.810 4.000 93.190 4.280 ;
        RECT 94.030 4.000 96.410 4.280 ;
        RECT 97.250 4.000 99.630 4.280 ;
        RECT 100.470 4.000 102.850 4.280 ;
        RECT 103.690 4.000 106.070 4.280 ;
        RECT 106.910 4.000 109.290 4.280 ;
        RECT 110.130 4.000 112.510 4.280 ;
        RECT 113.350 4.000 115.730 4.280 ;
        RECT 116.570 4.000 122.170 4.280 ;
        RECT 123.010 4.000 125.390 4.280 ;
        RECT 126.230 4.000 138.270 4.280 ;
        RECT 139.110 4.000 141.490 4.280 ;
        RECT 142.330 4.000 151.150 4.280 ;
        RECT 151.990 4.000 157.590 4.280 ;
        RECT 158.430 4.000 160.810 4.280 ;
        RECT 161.650 4.000 164.030 4.280 ;
        RECT 164.870 4.000 167.250 4.280 ;
        RECT 168.090 4.000 170.470 4.280 ;
        RECT 171.310 4.000 173.690 4.280 ;
        RECT 174.530 4.000 176.910 4.280 ;
        RECT 177.750 4.000 180.130 4.280 ;
        RECT 180.970 4.000 183.350 4.280 ;
        RECT 184.190 4.000 186.570 4.280 ;
        RECT 187.410 4.000 189.790 4.280 ;
        RECT 190.630 4.000 244.530 4.280 ;
        RECT 245.370 4.000 250.970 4.280 ;
        RECT 251.810 4.000 254.190 4.280 ;
        RECT 255.030 4.000 328.810 4.280 ;
      LAYER met3 ;
        RECT 3.990 310.440 330.440 332.005 ;
        RECT 3.990 309.040 330.040 310.440 ;
        RECT 3.990 303.640 330.440 309.040 ;
        RECT 3.990 302.240 330.040 303.640 ;
        RECT 3.990 300.240 330.440 302.240 ;
        RECT 4.400 298.840 330.440 300.240 ;
        RECT 3.990 293.440 330.440 298.840 ;
        RECT 3.990 292.040 330.040 293.440 ;
        RECT 3.990 286.640 330.440 292.040 ;
        RECT 3.990 285.240 330.040 286.640 ;
        RECT 3.990 269.640 330.440 285.240 ;
        RECT 3.990 268.240 330.040 269.640 ;
        RECT 3.990 266.240 330.440 268.240 ;
        RECT 3.990 264.840 330.040 266.240 ;
        RECT 3.990 262.840 330.440 264.840 ;
        RECT 3.990 261.440 330.040 262.840 ;
        RECT 3.990 259.440 330.440 261.440 ;
        RECT 4.400 258.040 330.040 259.440 ;
        RECT 3.990 256.040 330.440 258.040 ;
        RECT 3.990 254.640 330.040 256.040 ;
        RECT 3.990 252.640 330.440 254.640 ;
        RECT 4.400 251.240 330.440 252.640 ;
        RECT 3.990 249.240 330.440 251.240 ;
        RECT 4.400 247.840 330.440 249.240 ;
        RECT 3.990 245.840 330.440 247.840 ;
        RECT 4.400 244.440 330.440 245.840 ;
        RECT 3.990 242.440 330.440 244.440 ;
        RECT 4.400 241.040 330.440 242.440 ;
        RECT 3.990 239.040 330.440 241.040 ;
        RECT 4.400 237.640 330.440 239.040 ;
        RECT 3.990 235.640 330.440 237.640 ;
        RECT 4.400 234.240 330.440 235.640 ;
        RECT 3.990 232.240 330.440 234.240 ;
        RECT 4.400 230.840 330.440 232.240 ;
        RECT 3.990 228.840 330.440 230.840 ;
        RECT 4.400 227.440 330.440 228.840 ;
        RECT 3.990 225.440 330.440 227.440 ;
        RECT 4.400 224.040 330.440 225.440 ;
        RECT 3.990 222.040 330.440 224.040 ;
        RECT 4.400 220.640 330.440 222.040 ;
        RECT 3.990 218.640 330.440 220.640 ;
        RECT 4.400 217.240 330.440 218.640 ;
        RECT 3.990 215.240 330.440 217.240 ;
        RECT 4.400 213.840 330.040 215.240 ;
        RECT 3.990 211.840 330.440 213.840 ;
        RECT 4.400 210.440 330.440 211.840 ;
        RECT 3.990 208.440 330.440 210.440 ;
        RECT 4.400 207.040 330.040 208.440 ;
        RECT 3.990 205.040 330.440 207.040 ;
        RECT 4.400 203.640 330.040 205.040 ;
        RECT 3.990 201.640 330.440 203.640 ;
        RECT 4.400 200.240 330.040 201.640 ;
        RECT 3.990 198.240 330.440 200.240 ;
        RECT 4.400 196.840 330.440 198.240 ;
        RECT 3.990 191.440 330.440 196.840 ;
        RECT 3.990 190.040 330.040 191.440 ;
        RECT 3.990 188.040 330.440 190.040 ;
        RECT 3.990 186.640 330.040 188.040 ;
        RECT 3.990 184.640 330.440 186.640 ;
        RECT 3.990 183.240 330.040 184.640 ;
        RECT 3.990 181.240 330.440 183.240 ;
        RECT 4.400 179.840 330.440 181.240 ;
        RECT 3.990 177.840 330.440 179.840 ;
        RECT 4.400 176.440 330.040 177.840 ;
        RECT 3.990 174.440 330.440 176.440 ;
        RECT 4.400 173.040 330.440 174.440 ;
        RECT 3.990 171.040 330.440 173.040 ;
        RECT 4.400 169.640 330.440 171.040 ;
        RECT 3.990 167.640 330.440 169.640 ;
        RECT 4.400 166.240 330.440 167.640 ;
        RECT 3.990 164.240 330.440 166.240 ;
        RECT 4.400 162.840 330.440 164.240 ;
        RECT 3.990 160.840 330.440 162.840 ;
        RECT 4.400 159.440 330.040 160.840 ;
        RECT 3.990 157.440 330.440 159.440 ;
        RECT 4.400 156.040 330.040 157.440 ;
        RECT 3.990 154.040 330.440 156.040 ;
        RECT 4.400 152.640 330.040 154.040 ;
        RECT 3.990 150.640 330.440 152.640 ;
        RECT 3.990 149.240 330.040 150.640 ;
        RECT 3.990 147.240 330.440 149.240 ;
        RECT 3.990 145.840 330.040 147.240 ;
        RECT 3.990 143.840 330.440 145.840 ;
        RECT 3.990 142.440 330.040 143.840 ;
        RECT 3.990 140.440 330.440 142.440 ;
        RECT 4.400 139.040 330.040 140.440 ;
        RECT 3.990 137.040 330.440 139.040 ;
        RECT 3.990 135.640 330.040 137.040 ;
        RECT 3.990 133.640 330.440 135.640 ;
        RECT 3.990 132.240 330.040 133.640 ;
        RECT 3.990 130.240 330.440 132.240 ;
        RECT 3.990 128.840 330.040 130.240 ;
        RECT 3.990 126.840 330.440 128.840 ;
        RECT 3.990 125.440 330.040 126.840 ;
        RECT 3.990 123.440 330.440 125.440 ;
        RECT 3.990 122.040 330.040 123.440 ;
        RECT 3.990 120.040 330.440 122.040 ;
        RECT 3.990 118.640 330.040 120.040 ;
        RECT 3.990 116.640 330.440 118.640 ;
        RECT 3.990 115.240 330.040 116.640 ;
        RECT 3.990 109.840 330.440 115.240 ;
        RECT 3.990 108.440 330.040 109.840 ;
        RECT 3.990 103.040 330.440 108.440 ;
        RECT 3.990 101.640 330.040 103.040 ;
        RECT 3.990 99.640 330.440 101.640 ;
        RECT 3.990 98.240 330.040 99.640 ;
        RECT 3.990 96.240 330.440 98.240 ;
        RECT 4.400 94.840 330.440 96.240 ;
        RECT 3.990 92.840 330.440 94.840 ;
        RECT 3.990 91.440 330.040 92.840 ;
        RECT 3.990 89.440 330.440 91.440 ;
        RECT 4.400 88.040 330.040 89.440 ;
        RECT 3.990 86.040 330.440 88.040 ;
        RECT 4.400 84.640 330.040 86.040 ;
        RECT 3.990 82.640 330.440 84.640 ;
        RECT 3.990 81.240 330.040 82.640 ;
        RECT 3.990 79.240 330.440 81.240 ;
        RECT 3.990 77.840 330.040 79.240 ;
        RECT 3.990 75.840 330.440 77.840 ;
        RECT 3.990 74.440 330.040 75.840 ;
        RECT 3.990 72.440 330.440 74.440 ;
        RECT 3.990 71.040 330.040 72.440 ;
        RECT 3.990 69.040 330.440 71.040 ;
        RECT 3.990 67.640 330.040 69.040 ;
        RECT 3.990 65.640 330.440 67.640 ;
        RECT 3.990 64.240 330.040 65.640 ;
        RECT 3.990 62.240 330.440 64.240 ;
        RECT 3.990 60.840 330.040 62.240 ;
        RECT 3.990 58.840 330.440 60.840 ;
        RECT 3.990 57.440 330.040 58.840 ;
        RECT 3.990 45.240 330.440 57.440 ;
        RECT 3.990 43.840 330.040 45.240 ;
        RECT 3.990 41.840 330.440 43.840 ;
        RECT 3.990 40.440 330.040 41.840 ;
        RECT 3.990 10.715 330.440 40.440 ;
      LAYER met4 ;
        RECT 63.775 13.095 174.240 324.865 ;
        RECT 176.640 13.095 177.540 324.865 ;
        RECT 179.940 13.095 253.625 324.865 ;
  END
END compute_core
END LIBRARY

